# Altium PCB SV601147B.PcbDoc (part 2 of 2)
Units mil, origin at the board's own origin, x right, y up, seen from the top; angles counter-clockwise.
Board outline 2155 x 1865 mil, 4 copper layers (Top Layer, MidLayer1, MidLayer2, Bottom Layer), stack 61.2 mil thick; 86 components, 54 nets, 303 pads, 97 vias.

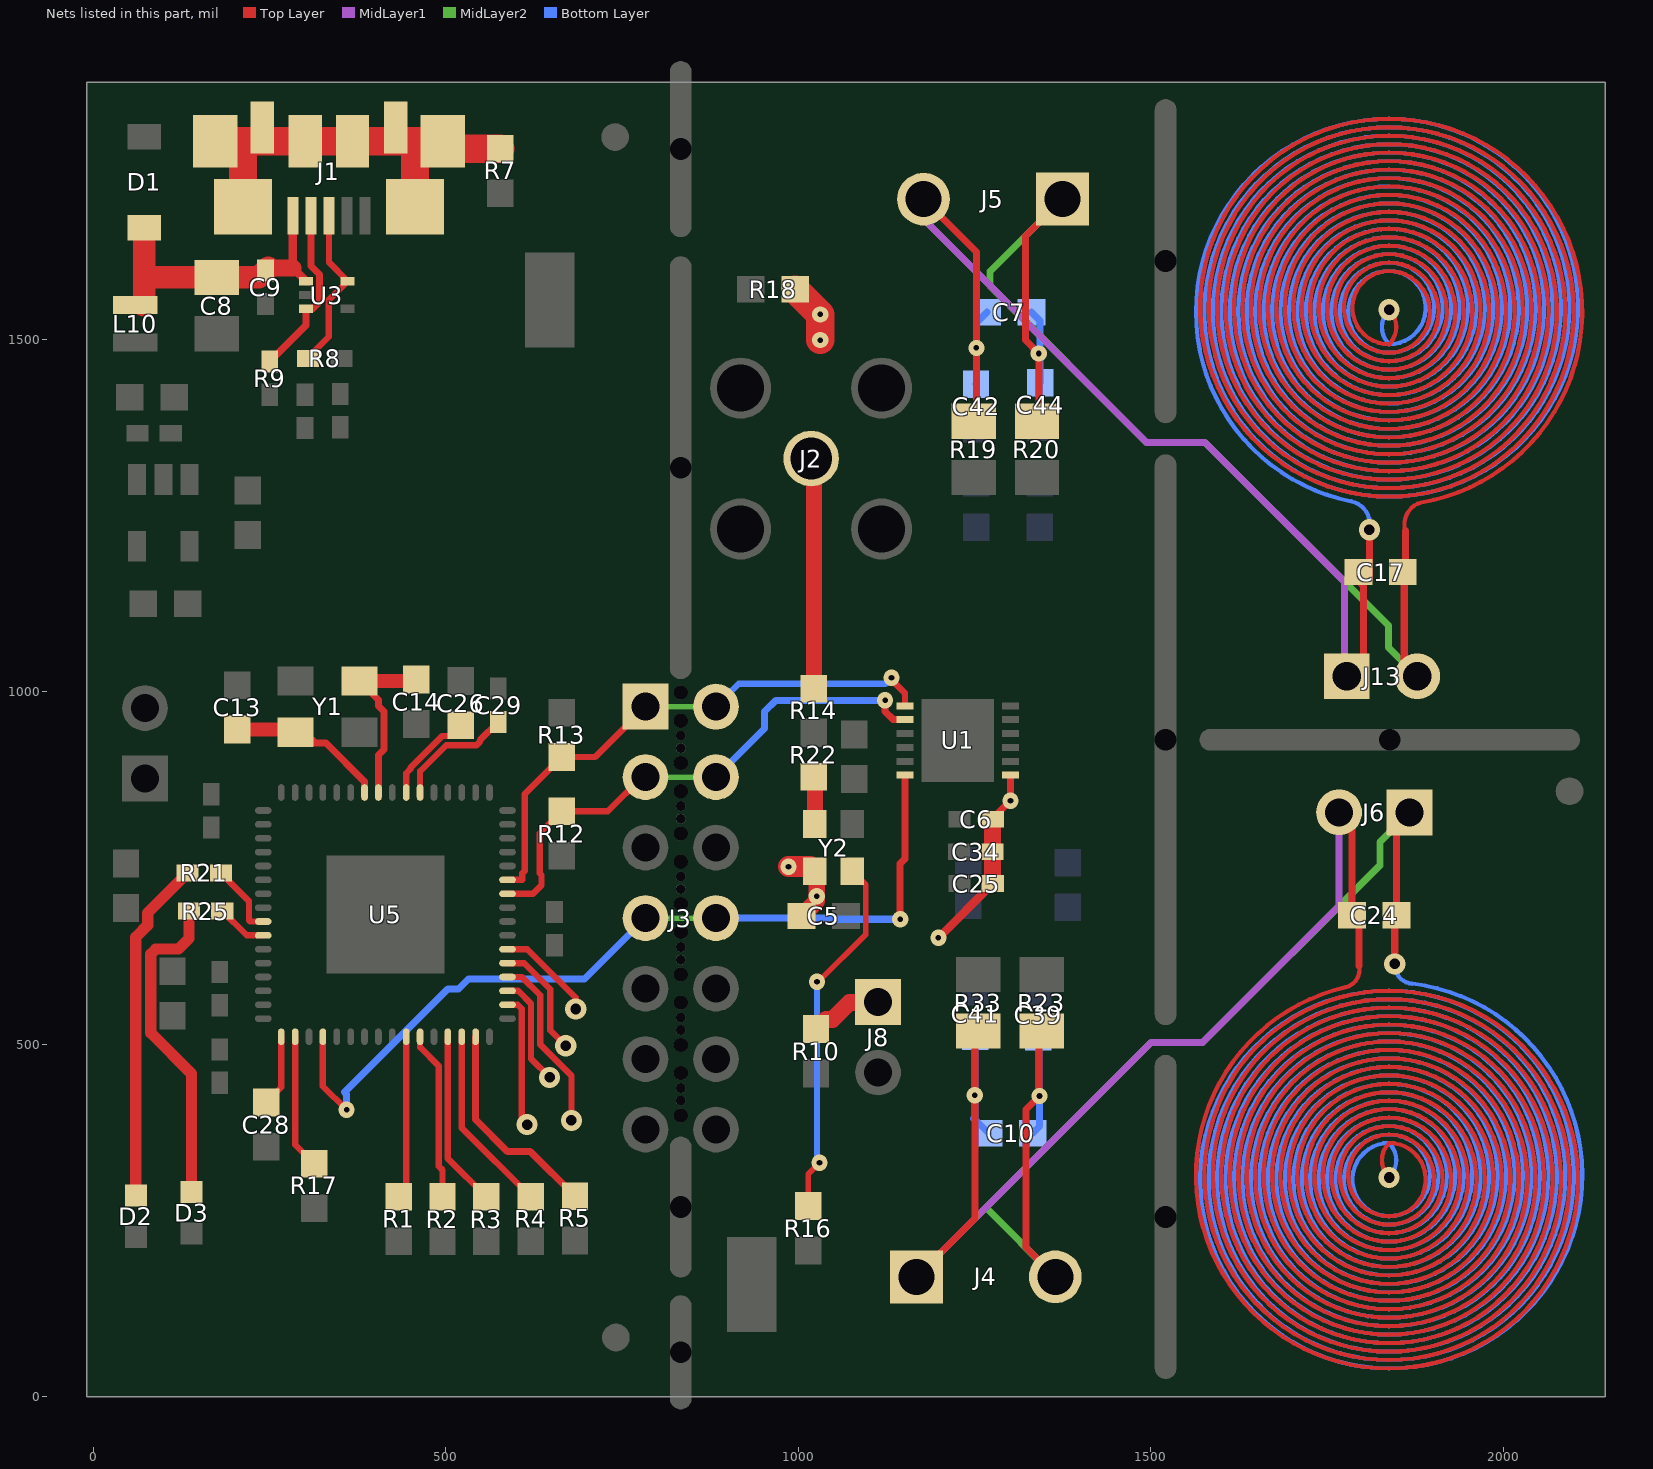
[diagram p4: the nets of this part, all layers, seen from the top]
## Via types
v1: diameter 23, hole 8, Top Layer to Bottom Layer, tented both sides, 58 vias
v2: diameter 19.68, hole 7.87, Top Layer to Bottom Layer, 18 vias
v3: diameter 20, hole 8, Top Layer to Bottom Layer, tented both sides, 8 vias
v4: diameter 30, hole 15, Top Layer to Bottom Layer, 5 vias
v5: diameter 30, hole 15, Top Layer to Bottom Layer, tented both sides, 4 vias
v6: diameter 50, hole 25, Top Layer to Bottom Layer, 2 vias
v7: diameter 50, hole 28, Top Layer to Bottom Layer, 2 vias

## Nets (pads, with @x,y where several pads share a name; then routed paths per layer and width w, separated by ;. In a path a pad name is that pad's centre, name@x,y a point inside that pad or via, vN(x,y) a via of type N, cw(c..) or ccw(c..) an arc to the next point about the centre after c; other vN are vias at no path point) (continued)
NetC7_1: C7.1 C7.2 C17.1 C17.2 C42.2 C44.1 J5.1 J5.2 J13.1 J13.2 R19.2 R20.2 | length 42394.5
  Top Layer w6: v5(1838,1542) cw(c1813.5,1517.5) 1838,1493 cw(c1838,1545) 1838,1597 cw(c1838,1539) 1838,1481 cw(c1838,1545) 1838,1609 cw(c1838,1539) 1838,1469 cw(c1838,1545) 1838,1621 cw(c1838,1539) 1838,1457 cw(c1838,1545) 1838,1633 cw(c1838,1539) 1838,1445 cw(c1838,1545) 1838,1645 cw(c1838,1539) 1838,1433 cw(c1838,1545) 1838,1657 cw(c1838,1539) 1838,1421 cw(c1838,1545) 1838,1669 cw(c1838,1539) 1838,1409 cw(c1838,1545) 1838,1681 cw(c1838,1539) 1838,1397 cw(c1838,1545) 1838,1693 cw(c1838,1539) 1838,1385 cw(c1838,1545) 1838,1705 cw(c1838,1539) 1838,1373 cw(c1838,1545) 1838,1717 cw(c1838,1539) 1838,1361 cw(c1838,1545) 1838,1729 cw(c1838,1539) 1838,1349 cw(c1838,1545) 1838,1741 cw(c1838,1539) 1838,1337 cw(c1838,1545) 1838,1753 cw(c1838,1539) 1838,1325 cw(c1838,1545) 1838,1765 cw(c1838,1539) 1838,1313 cw(c1838,1545) 1838,1777 cw(c1838,1539) 1838,1301 cw(c1838,1545) 1838,1789 cw(c1838,1539) 1838,1289 cw(c1838,1545) 1838,1801 cw(c1838,1539) 1838,1277 cw(c1838,1545) 1838,1813 cw(c1838,1539) 1883.53,1268.81 ccw(c1892.17,1237.64) 1861,1229
  Top Layer w10: J5.2@1177.57,1699 1252.46,1624.12 v1(1252.46,1488) R19.2@1252.46,1381 ; R20.2@1342.46,1384 1341,1385.46 v1(1341,1480) 1322,1499 1322,1646.57 J5.1@1368.71,1693.29 ; J13.1@1777,1003 1777,1004 1802,1029 1802,1149.5 C17.1@1796.5,1155 ; C17.1@1810,1158.5 v5(1810,1230) ; J13.2@1859.5,1020.5 C17.2@1859.5,1155 ; C17.2@1861,1163.5 1861,1229 ; J13.2@1870,1010 J13.2@1877,1003
  MidLayer1 w10: J5.2@1157.57,1690.43 1494,1354 1577,1354 1775,1156 J13.1@1775,1015 ; J5.2@1177.57,1690.43 J5.2@1177.57,1699
  MidLayer2 w10: J5.1@1374.43,1699 1271.71,1596.29 1271.71,1576.71 1271.5,1576.5 1494,1354 1577,1354 1837,1094 1837,1063 J13.2@1878,1022
  Bottom Layer w6: v5(1810,1230) ccw(c1777.09,1237.37) 1784.45,1270.28 cw(c1838,1539) 1838,1813 cw(c1838,1545) 1838,1277 cw(c1838,1539) 1838,1801 cw(c1838,1545) 1838,1289 cw(c1838,1539) 1838,1789 cw(c1838,1545) 1838,1301 cw(c1838,1539) 1838,1777 cw(c1838,1545) 1838,1313 cw(c1838,1539) 1838,1765 cw(c1838,1545) 1838,1325 cw(c1838,1539) 1838,1753 cw(c1838,1545) 1838,1337 cw(c1838,1539) 1838,1741 cw(c1838,1545) 1838,1349 cw(c1838,1539) 1838,1729 cw(c1838,1545) 1838,1361 cw(c1838,1539) 1838,1717 cw(c1838,1545) 1838,1373 cw(c1838,1539) 1838,1705 cw(c1838,1545) 1838,1385 cw(c1838,1539) 1838,1693 cw(c1838,1545) 1838,1397 cw(c1838,1539) 1838,1681 cw(c1838,1545) 1838,1409 cw(c1838,1539) 1838,1669 cw(c1838,1545) 1838,1421 cw(c1838,1539) 1838,1657 cw(c1838,1545) 1838,1433 cw(c1838,1539) 1838,1645 cw(c1838,1545) 1838,1445 cw(c1838,1539) 1838,1633 cw(c1838,1545) 1838,1457 cw(c1838,1539) 1838,1621 cw(c1838,1545) 1838,1469 cw(c1838,1539) 1838,1609 cw(c1838,1545) 1838,1481 cw(c1838,1539) 1838,1597 cw(c1838,1545) 1838,1493 cw(c1862.5,1517.5) v5(1838,1542)
  Bottom Layer w10: C42.2@1252,1436.5 1252.46,1436.95 v1(1252.46,1488) 1252.46,1523.52 C7.2@1267.5,1538.57 ; C7.1@1330.5,1538.57 1342.46,1526.61 1342.46,1439.04 C44.1@1343,1438.5 ; J13.2@1861.33,1012.08 J13.2@1871,1012
NetC10_1: C10.1 C10.2 C24.1 C24.2 C39.2 C41.1 J4.1 J4.2 J6.1 J6.2 R23.2 R33.2 | length 42470.1
  Top Layer w6: 1795.37,610.97 cw(c1770.52,605.69) 1775.8,580.85 ccw(c1838,314) 1838,40 ccw(c1838,308) 1838,576 ccw(c1838,314) 1838,52 ccw(c1838,308) 1838,564 ccw(c1838,314) 1838,64 ccw(c1838,308) 1838,552 ccw(c1838,314) 1838,76 ccw(c1838,308) 1838,540 ccw(c1838,314) 1838,88 ccw(c1838,308) 1838,528 ccw(c1838,314) 1838,100 ccw(c1838,308) 1838,516 ccw(c1838,314) 1838,112 ccw(c1838,308) 1838,504 ccw(c1838,314) 1838,124 ccw(c1838,308) 1838,492 ccw(c1838,314) 1838,136 ccw(c1838,308) 1838,480 ccw(c1838,314) 1838,148 ccw(c1838,308) 1838,468 ccw(c1838,314) 1838,160 ccw(c1838,308) 1838,456 ccw(c1838,314) 1838,172 ccw(c1838,308) 1838,444 ccw(c1838,314) 1838,184 ccw(c1838,308) 1838,432 ccw(c1838,314) 1838,196 ccw(c1838,308) 1838,420 ccw(c1838,314) 1838,208 ccw(c1838,308) 1838,408 ccw(c1838,314) 1838,220 ccw(c1838,308) 1838,396 ccw(c1838,314) 1838,232 ccw(c1838,308) 1838,384 ccw(c1838,314) 1838,244 ccw(c1838,308) 1838,372 ccw(c1838,314) 1838,256 ccw(c1838,308) 1838,360 ccw(c1862.5,335.5) v5(1838,311)
  Top Layer w10: J4.1@1167.57,170 1250.3,252.72 v1(1250.3,427.55) R33.2@1250.3,519 ; v1@1341,427.55 R23.2@1341,521 ; v1(1342,426.55) 1322.71,407.26 1322.71,211.71 J4.2@1364.43,170 ; J6.2@1767,829 1785.5,810.5 C24.1@1785.5,684 ; 1795.37,610.97 C24.1@1795.37,673.14 ; v5(1846,614) C24.2@1846,681.5 ; C24.2@1848.5,683 1848.5,684 1848.5,810.5 J6.1@1867,829
  MidLayer1 w10: J4.1@1167.57,170 1500,502.43 1573.43,502.43 1767,696 J6.2@1767,829
  MidLayer2 w10: J4.2@1364.43,170 1266,268.43 1500,502.43 1573.43,502.43 1825,754 1825,787 J6.1@1867,829
  Bottom Layer w6: v5(1838,311) ccw(c1813.5,335.5) 1838,360 ccw(c1838,308) 1838,256 ccw(c1838,314) 1838,372 ccw(c1838,308) 1838,244 ccw(c1838,314) 1838,384 ccw(c1838,308) 1838,232 ccw(c1838,314) 1838,396 ccw(c1838,308) 1838,220 ccw(c1838,314) 1838,408 ccw(c1838,308) 1838,208 ccw(c1838,314) 1838,420 ccw(c1838,308) 1838,196 ccw(c1838,314) 1838,432 ccw(c1838,308) 1838,184 ccw(c1838,314) 1838,444 ccw(c1838,308) 1838,172 ccw(c1838,314) 1838,456 ccw(c1838,308) 1838,160 ccw(c1838,314) 1838,468 ccw(c1838,308) 1838,148 ccw(c1838,314) 1838,480 ccw(c1838,308) 1838,136 ccw(c1838,314) 1838,492 ccw(c1838,308) 1838,124 ccw(c1838,314) 1838,504 ccw(c1838,308) 1838,112 ccw(c1838,314) 1838,516 ccw(c1838,308) 1838,100 ccw(c1838,314) 1838,528 ccw(c1838,308) 1838,88 ccw(c1838,314) 1838,540 ccw(c1838,308) 1838,76 ccw(c1838,314) 1838,552 ccw(c1838,308) 1838,64 ccw(c1838,314) 1838,564 ccw(c1838,308) 1838,52 ccw(c1838,314) 1838,576 ccw(c1838,308) 1838,40 ccw(c1838,314) 1871,586.01 cw(c1872.5,612.5) v5(1846,614)
  Bottom Layer w10: C41.1@1251,511.5 1250.3,510.8 v1(1250.3,427.55) 1250.3,396.44 1248.68,394.82 C10.2@1269.5,374 ; C10.1@1332.5,374 1342,383.5 v1(1342,426.55) ; C39.2@1340,510.5 1341,509.5 v1@1341,427.55 ; J6.2@1767,829 J6.2@1781,829 ; J6.1@1849,829 J6.1@1864.28,829 ; J6.1@1865.64,830.36 J6.1@1864.28,829 ; J6.1@1867,829 J6.1@1864.28,829
NetC13_2: C13.2 U5.58 Y1.3 | length 226.3
  Top Layer w10: Y1.3@286.72,942.58 299.11,942.58 314.44,927.26 329.64,927.26 384.46,872.43 U5.58@384.46,857.23
  Top Layer w20: C13.2@204,946.5 282.8,946.5 Y1.3@286.72,942.58
NetC14_2: C14.2 U5.57 Y1.1 | length 257.3
  Top Layer w10: Y1.1@377.28,1015.42 404.15,988.54 404.15,979.96 411.87,972.25 411.87,918.19 404.15,910.47 U5.57@404.15,857.23
  Top Layer w20: Y1.1@377.28,1015.42 455.92,1015.42 C14.2@458,1017.5
NetC26_2: C26.2 U5.55 | length 140.8
  Top Layer w9: U5.55@443.54,857.23 443.54,884.53 450.22,891.22 450.22,892.61 494.93,937.32 517.79,937.32 521,940.53 C26.2@521,952.5
NetC28_1: C28.1 U5.17 | length 102.3
  Top Layer w9: C28.1@245,417.5 266.5,439 266.5,510.6 U5.17@266.33,510.77
NetD2_1: D2.1 R21.2 | length 487.9
  Top Layer w16: D2.1@60,285.53 60,652.15 76.7,668.85 76.7,686.32 R21.2@133.38,743
NetD3_1: D3.1 R25.2 | length 463.6
  Top Layer w16: R25.2@135.38,689 135.38,650.13 120.43,635.18 88.33,635.18 81.3,628.15 81.3,515.85 139,458.15 139,304.53 D3.1@139,290.53
NetJ1_2: J1.2 R9.1 U3.3 | length 246.1
  Top Layer w10: R9.1@250,1468.62 301.47,1520.09 U3.3@301.47,1543.32 310.26,1543.32 320.31,1553.37 320.31,1592.32 308.41,1604.22 J1.2@308.41,1675.49
NetJ1_3: J1.3 R8.1 U3.5 | length 236.7
  Top Layer w9: R8.1@304.38,1473 304.38,1474.47 333.81,1503.91 333.81,1555.97 U3.5@360.53,1582.69 334,1609.21 J1.3@334,1675.49
NetJ1_6: J1.6 J1.7 J1.8 J1.9 J1.10 J1.11 J1.12 J1.13 R7.2 | length 725
  Top Layer w40: J1.13@178,1781 J1.8@495.42,1781 ; J1.7@211.95,1688.48 211.95,1779.95 ; 211.95,1781 J1.11@300.54,1781 J1.10@367.46,1781 ; J1.6@456.05,1688.48 456.05,1777.95 ; J1.8@505.92,1770.5 R7.2@577,1770.5
NetJ2_1: J2.1 R14.2 | length 328.2
  Top Layer w23: J2.1@1018,1331 1022,1327 R14.2@1022,1004.5
NetR1_1: R1.1 U5.26 | length 231.6
  Top Layer w9: R1.1@433,283.5 443.54,294.03 U5.26@443.54,510.77
NetR2_1: R2.1 U5.27 | length 240.4
  Top Layer w9: U5.27@463.22,510.77 463.22,495.57 489.61,469.19 489.61,327.11 495,321.72 R2.1@495,283.5
NetR3_1: R3.1 U5.29 | length 249.8
  Top Layer w9: U5.29@502.61,510.77 502.61,337.89 R3.1@557,283.5
NetR4_1: R4.1 U5.30 | length 267.7
  Top Layer w9: U5.30@522.3,510.77 522.3,381.2 R4.1@620,283.5
NetR5_1: R5.1 U5.31 | length 303.7
  Top Layer w10: U5.31@541.98,510.77 541.98,393.02 587,348 619.5,348 R5.1@683,284.5
NetR16_2: R16.2 Y2.1 | length 520.9
  Top Layer w8: R16.2@1014,270.5 1014,316 v1(1030,332) ; v1(1026.4,588.82) 1028.71,588.82 1095.43,655.55 1095.43,726.68 Y2.1@1076.57,745.54
  Bottom Layer w8: v1(1026.4,588.82) 1026.4,335.6 v1(1030,332)
NetR17_1: R17.1 U5.18 | length 191.5
  Top Layer w9: U5.18@286.01,510.77 286.01,357.48 R17.1@313,330.5
NetR21_1: R21.1 U5.9 | length 104.7
  Top Layer w9: R21.1@180.62,743 220.46,703.16 220.46,675.85 222.16,674.16 U5.9@240.77,674.16
NetR22_1: R22.1 Y2.3 | length 67.6
  Top Layer w23: R22.1@1022,879.5 1023.43,878.08 Y2.3@1023.43,812.46
NetR25_1: R25.1 U5.10 | length 72.5
  Top Layer w9: R25.1@182.62,689 217.15,654.47 U5.10@240.77,654.47
P3.0: U5.34 | length 190.2
  Top Layer w9: U5.34@587.23,556.05 601.95,556.05 607.54,550.46 607.54,393.46 v4(615,386)
P3.1: U5.35 | length 156.3
  Top Layer w9: U5.35@587.23,575.73 602.27,575.73 620.54,557.46 620.54,479.46 v4(647,453)
P3.2: U5.36 | length 252.9
  Top Layer w9: U5.36@587.23,595.42 607.58,595.42 633.54,569.46 633.54,499.69 678,455.23 v4(678,392)
P3.3: U5.37 | length 165.3
  Top Layer w9: U5.37@587.23,615.1 610.9,615.1 648,578 648,520 v4(670,498)
P3.4: U5.38 | length 141.3
  Top Layer w9: U5.38@587.23,634.79 615.21,634.79 684,566 v4(684,550)
SCL: J3.1 J3.2 R13.1 U1.1 U5.43 | length 784.9
  Top Layer w9: U5.43@587.23,733.21 608.21,733.21 608.21,742.44 611.54,745.76 611.54,855.04 R13.1@664,907.5 711.5,907.5 J3.1@783,979 ; v1(1132,1020) 1132,1017.39 1151.2,998.2 U1.1@1151.2,980.21
  MidLayer1 w9: v1(1132,1020) v1@1136.14,1020
  MidLayer2 w8: J3.1@783,979 J3.2@883,979
  Bottom Layer w9: J3.2@883,979 915.5,1011.5 1123.5,1011.5 v1(1132,1020)
SD: J3.7 J3.8 U1.6 U5.20 | length 1232.4
  Top Layer w9: U5.20@325.39,510.77 325.39,440.61 v1(359,407)
  Top Layer w10: v1(1144.39,677.39) 1144.39,756.39 1151.2,763.2 U1.6@1151.2,881.79
  MidLayer2 w8: J3.7@783,679 J3.8@873,679
  Bottom Layer w10: v1(359,407) 359,429.08 356.08,432 502.58,578.5 517.8,578.5 531.8,592.5 696.5,592.5 J3.7@783,679 ; J3.8@883,679 944,679 1052,679 1053.61,677.39 v1(1144.39,677.39)
SDA: J3.3 J3.4 R12.1 U1.2 U5.42 | length 759.5
  Top Layer w9: U5.42@587.23,713.53 623.53,713.53 635.46,725.46 635.46,739.98 632.8,742.64 632.8,799.3 R12.1@664,830.5 729.5,830.5 778,879 J3.3@783,879
  Top Layer w10: v1(1123,988) 1123,972 1134.47,960.53 U1.2@1151.2,960.53
  MidLayer2 w8: J3.3@783,879 J3.4@883,879
  Bottom Layer w10: J3.4@883,879 952,948 952,972 968,988 v1(1123,988)
VBUS: C8.1 C9.1 D1.1 J1.1 L10.1 U3.1 | length 429.4
  Top Layer w12: J1.1@282.82,1675.49 282.82,1601.34 U3.1@301.47,1582.69
  Top Layer w24: C9.1@247.72,1601.34 282.82,1601.34
  Top Layer w32: L10.1@71,1548.57 72,1549.57 72,1593.32 ; D1.1@72,1658.53 72,1593.32 ; C9.1@247.72,1601.34 C9.1@244,1597.62 234.38,1588 C8.1@175,1588 77.32,1588 72,1593.32
VDD: C5.1 C6.1 C25.1 C34.1 J8.1 R10.2 R18.2 U1.7 Y2.4 | length 561.4
  Top Layer w10: C6.1@1275.22,820 v1(1300.8,845.58) U1.7@1300.8,881.79
  Top Layer w12: v1(1198.62,651) C25.1@1275.62,728
  Top Layer w24: C5.1@1004.5,682 1026,703.5 1026,742.96 Y2.4@1023.43,745.54 ; R10.2@1025,521.5 1038.83,535.32 1048.56,535.32 1072.42,559.18 1113,559.18 J8.1@1113,560 ; C34.1@1275.22,773 1275.22,728.4 C25.1@1275.62,728 ; C34.1@1275.22,775 1275.22,805.19
  Top Layer w30: v1(986,752) 1016.96,752 Y2.4@1023.43,745.54
  Top Layer w40: R18.2@995.5,1571 v1(1031,1535.5) v1(1031,1499)
  other v1: 1026,710
VUSB: C29.1 U5.54 | length 171.2
  Top Layer w9: U5.54@463.22,857.23 463.22,887.22 500.32,924.32 543.22,924.32 548.2,929.3 548.2,931.58 C29.1@574,957.38
pads on no net: FID1.1 FID2.1 FID3.1 J1.4 LBL1.0 U3.2 U5.1 U5.2 U5.3 U5.4 U5.5 U5.6 U5.7 U5.8 U5.12 U5.13 U5.22 U5.23 U5.24 U5.25 U5.28 U5.32 U5.33 U5.41 U5.44 U5.45 U5.46 U5.47 U5.48

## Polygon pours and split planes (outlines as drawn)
GND on MidLayer1 "Bottom Layer-No Net" (solid, pour order 11): 19.09,-7.34 792.09,-7.34 792.09,1812.66 19.09,1812.66 19.09,-7.34
GND on MidLayer1 "Bottom Layer-No Net" (solid, remove dead copper, pour order 14): 875,35 1541,35 1541,1840 875,1840 875,35
+3.3V on MidLayer2 "Bottom Layer-No Net" (solid, pour order 8): 20,770 790,770 790,1840 20,1840
+3.3V on MidLayer2 "Bottom Layer-No Net" (solid, pour order 10): 17,17 791,17 791,770.5 17,770.5 17,17
+3.3V on MidLayer2 "Bottom Layer-No Net" (solid, remove dead copper, pour order 13): 875,35 1539,35 1539,1840 875,1840 875,35
VDD on MidLayer2 "Bottom Layer-No Net" (solid, remove dead copper, pour order 12): 972.46,510 1388.46,510 1388.46,1725.95 972.46,1725.95
GND on Bottom Layer "Bottom Layer-No Net 1" (solid, remove dead copper, pour order 9): 899,368.67 1399,368.67 1399,1476.67 899,1476.67

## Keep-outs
Keep-Out Layer:
  lines w8: -15,-5 2150,-5 2150,1870 -15,1870 -15,-5
  text ".Layer_Name" at 577,-858.49 h60

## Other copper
Top Layer:
  text ".Layer_Name" at 577,-858.49 h60
MidLayer1:
  pour cut-out: 154.5,894 154.7,894.2 154.7,1052.87 485.63,1052.87 497.5,1040.99 497.5,888
  pour cut-out: 876,1185.33 876,1470 1163.67,1470 1163.67,1186 1163,1185.33
MidLayer2:
  pour cut-out: 154.5,894 154.7,894.2 154.7,1052.87 485.63,1052.87 497.5,1040.99 497.5,888
Bottom Layer:
  text ".Layer_Name" at 577,-858.49 h60
Multi-Layer:
  pour cut-out: 1288,311 ccw(c1838,311) 1838,-239 ccw(c1838,311) 2388,311 ccw(c1838,311) 1838,861 ccw(c1838,311)
  pour cut-out: 1838,992 cw(c1838,1542) 1288,1542 cw(c1838,1542) 1838,2092 cw(c1838,1542) 2388,1542 cw(c1838,1542)

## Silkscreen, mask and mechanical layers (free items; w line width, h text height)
Top Overlay:
  lines w10: 1123,693 1420,693 1420,1086 1123,1086 1123,693
  text "GND" at 897,1808 h30
  text "CH1" at 1334,1454 h60
  text "GND" at 602,1425 h30
  text "SENSOR CH1" at 1670,1264 h55 r90
  text "+5V" at 417,1165 h30
  text "LDC" at 1289,1030 h40
  text "or" at 972.46,946.05 h30 r90
  text "SBW" at 161,898 h25 r90
  text "+3.3V" at 1204,438 h30 r90
  text "CH0" at 1308,351 h60
  text "GND" at 891,255 h30
  text "SENSOR CH0" at 1670,64 h55 r90
  text "GND" at 179,52 h30
  text "ACLK" at 360,43 h30 r90
  text ".Layer_Name" at 577,-858.49 h60
Bottom Overlay:
  region: 267,589 267,889 167,889 167,589
  text ".PRJ_Number" at 267,1805 h60 r90
  text "0.15mm trace width" at 2015,1804 h40 r90
  text "0.15mm trace spacing" at 2073,1804 h40 r90
  text "19 turns/layer" at 1899,1803 h40 r90
  text "2 layers" at 1957,1803 h40 r90
  text "SENSOR: 13.9mm" at 1841,1802 h40 r90
  text ".PCB_Rev" at 267,1292 h60 r90
  text "TCK" at 100,1042 h25
  text "SCL" at 1015,968 h30
  text "SDA" at 1024.37,865 h30
  text "TDIO" at 113,791 h25
  text "©" at 1998,768 h105 r90
  text "ADDR" at 1060.3,762 h30
  text "MADE IN U.S." at 2102,760 h60 r90
  text ".CopyrightYear" at 1986,677 h60 r90
  text "SD" at 1010,660 h30
  text "INTB" at 1045,565 h30
  text "GND" at 1018.25,469.61 h30
  text "3.3V" at 1046,363 h30
  text ".Layer_Name" at 577,-858.49 h60
Top Paste:
  text ".Layer_Name" at 577,-858.49 h60
Bottom Paste:
  text ".Layer_Name" at 577,-858.49 h60
Top Solder:
  text ".Layer_Name" at 577,-858.49 h60
  text ".Layer_Name" at 577,-858.49 h60
Bottom Solder:
  text ".Layer_Name" at 577,-858.49 h60
Drill Guide:
  text ".Layer_Name" at 577,-858.49 h60
M1 Board Outline:
  the board outline again, w8
  text ".Layer_Name" at 577,-858.49 h60
M2 Board Dimensions:
  rectangle: 124.5,-410.5 499.5,-285.5
  rectangle: -0.5,-285.5 124.5,-160.5
  lines w7: -0.5,-285.5 999.5,-285.5 ; 124.5,-410.5 124.5,-160.5 ; 249.5,-410.5 249.5,-160.5 ; 499.5,-410.5 499.5,-160.5 ; 749.5,-410.5 749.5,-160.5 ; -0.5,-410.5 -0.5,-160.5 999.5,-160.5 999.5,-410.5 -0.5,-410.5
  lines w10: -0.5,-475.5 -0.5,-455.5 ; 59.5,-485.5 -0.5,-465.5 ; 59.5,-445.5 -0.5,-465.5 ; 223.58,-465.5 -0.5,-465.5 ; 775.42,-465.5 999.5,-465.5 ; 939.5,-485.5 999.5,-465.5 ; 939.5,-445.5 999.5,-465.5 ; 999.5,-475.5 999.5,-455.5
  text "1000 (mil)" at 233.58,-501.49 h60
  text ".Layer_Name" at 577,-858.49 h60
M3 3D STEP Top:
  text ".Layer_Name" at 577,-858.49 h60
M4 3D STEP Bottom:
  text ".Layer_Name" at 577,-858.49 h60
M5 Assembly Top:
  lines w10: -292,-930.17 6308,-930.17 ; -292,-726.83 6310,-726.83 ; -292,-523.5 -292,-1133.5 3713,-1133.5 6310,-1133.5 6310,-523.5 -291.5,-523.5 -291.5,-1133.5 1284,-1133.5 ; 2173,-1133.5 2173,-523.5 ; 3440,-726.83 3440,-523.5 ; 4280,-726.83 4280,-523.5 ; 4902,-1140 4902,-937.17
  text "COMPONENTS MARKED 'DNP' SHOULD NOT BE POPULATED." at 1153.5,-318.5 h60
  text "ASSEMBLY VARIANT:" at 1153,-434 h60
  text ".VariantName" at 2189,-434 h60
  text "PCB VIEWED FROM TOP SIDE" at -228.5,-655.67 h60
  text "BOARD #:" at 2248,-655.67 h60
  text ".PRJ_Number" at 2793.5,-655.67 h60
  text "REV:" at 3638,-655.67 h60
  text ".PCB_Rev" at 3929.5,-655.67 h60
  text "SVN REV:" at 4476,-655.67 h60
  text ".VersionControl_RevNumber" at 4982,-655.67 h60
  text "IGNORE ->" at -228.5,-858.49 h60
  text "PLOT NAME =" at -228.5,-1064.34 h60
  text ".plot_File_Name" at 577,-1064.34 h60
  text "GENERATED    :" at 2250,-1064.34 h60
  text ".Print_Date" at 3119.5,-1064.34 h60
  text ".Print_Time" at 3848.5,-1064.34 h60
  text "TEXAS INSTRUMENTS" at 5113,-1064.34 h60
M6 Assembly Bottom:
  lines w10: -292.5,-727.33 6309.5,-727.33 ; -290.5,-930.67 6309.5,-930.67 ; 1115.5,-1140.5 1115.5,-937.67 ; 1737.5,-727.33 1737.5,-524 ; 2577.5,-727.33 2577.5,-524 ; 3844.5,-1134 3844.5,-524 ; 4733.5,-1134 6309,-1134 6309,-524 -292.5,-524 -292.5,-1134 2304.5,-1134 6309.5,-1134 6309.5,-524
  text "COMPONENTS MARKED 'DNP' SHOULD NOT BE POPULATED." at 6102,-318 h60
  text ".VariantName" at 5058,-434 h60
  text "ASSEMBLY VARIANT:" at 6097,-434 h60
  text ".VersionControl_RevNumber" at 1035.5,-656.17 h60
  text "SVN REV:" at 1541.5,-656.17 h60
  text ".PCB_Rev" at 2088,-656.17 h60
  text "REV:" at 2379.5,-656.17 h60
  text ".PRJ_Number" at 3224,-656.17 h60
  text "BOARD #:" at 3769.5,-656.17 h60
  text "PCB VIEWED FROM BOTTOM SIDE" at 6246,-656.17 h60
  text "IGNORE ->" at 2547.85,-858.49 h60
  text "TEXAS INSTRUMENTS" at 904.5,-1064.84 h60
  text ".Print_Time" at 2169,-1064.84 h60
  text ".Print_Date" at 2898,-1064.84 h60
  text "GENERATED    :" at 3767.5,-1064.84 h60
  text ".plot_File_Name" at 5440.5,-1064.84 h60
  text "PLOT NAME =" at 6246,-1064.84 h60
M9 Title Sheet:
  drawing of 54 lines, arcs and shapes, not listed
  text "1" at 739.84,8036.5 h70
  text "2" at 3235.5,8036.5 h70
  text "3" at 5724.84,8036.5 h70
  text "4" at 8231.51,8036.5 h70
  text "5" at 10730.5,8036.5 h70
  text "6" at 13235.5,8036.5 h70
  text "A" at -416.5,6893.5 h70
  text "A" at 14383.5,6893.5 h70
  text "B" at -416.5,4513.5 h70
  text "B" at 14383.5,4513.5 h70
  text "C" at -416.5,2138.5 h70
  text "C" at 14383.5,2138.5 h70
  text "PROJECT TITLE:" at 11343.5,277.5 h45
  text ".PRJ_Title" at 11393.5,144.17 h70
  text "DESIGNED FOR:" at 11343.5,-23.5 h45
  text ".PRJ_Customer" at 11393.5,-163.5 h70
  text "D" at -416.5,-231.5 h70
  text "D" at 14383.5,-231.5 h70
  text "FILE NAME:" at 11343.5,-323.5 h45
  text ".PCB_File_Name_No_Path" at 11393.5,-443.5 h70
  text "Texas Instruments (TI) and/or its licensors do not warrant the accuracy or completeness of this specification" at 6374,-605.34 h45
  text "ENGINEER:" at 11343.5,-613.5 h45
  text "LAYOUT BY:" at 12848.5,-613.5 h45
  text "or any information contained therein. TI and/or its licensors do not warrant that this design will meet" at 6329.01,-718 h45
  text ".PRJ_Engineer" at 11393.5,-768.49 h70
  text ".PCB_Layout" at 12899,-768.49 h70
  text "the specifications, will be suitable for your application or fit for any particular purpose, or will operate in" at 6329.01,-830.67 h45
  text ".Layer_Name" at 577,-858.49 h60
  text "ALTIUM DESIGNER VERSION:" at 12848.5,-923.5 h45
  text "an implementation. TI and/or its licensors do not warrant that the design is production worthy. You should" at 6329.01,-943.33 h45
  text "completely validate and test your design implementation to confirm the system functionality for your application." at 6374,-1056 h45
  text ".print_Scale" at 11393.5,-1056.83 h70
  text ".Application_BuildNumber" at 12899,-1056.83 h70
  text "1" at 739.84,-1263.5 h70
  text "2" at 3235.5,-1263.5 h70
  text "3" at 5724.84,-1263.5 h70
  text "4" at 8231.51,-1263.5 h70
  text "5" at 10730.5,-1263.5 h70
  text "6" at 13235.5,-1263.5 h70
M10 Fab Notes:
  drawing of 212 lines, arcs and shapes, not listed
  text "DESIGN INFORMATION" at 12381.02,6810 h60
  text "(REFER ALSO ARRAY/PANEL PROFILING INFORMATION)" at 12019.46,6648.29 h60
  text "BOARD SIZE" at 11333.46,6644 h60
  text "2145MIL" at 11795.78,6516.18 h60
  text "X" at 12301.46,6516.18 h60
  text "1865MIL" at 12532.78,6516.18 h60
  text "Number of Layers :" at 11736.46,6319 h60
  text "4" at 12831.27,6309 h60
  text "MIN. TRACK WIDTH:" at 11736.46,6180 h60
  text "4" at 12832.7,6180 h60
  text "MIL" at 12987.46,6180 h60
  text "MIN. CLEARANCE:" at 11736.46,6048 h60
  text "4" at 12832.7,6048 h60
  text "MIL" at 12987.46,6048 h60
  text "MIN. VIA PAD SIZE:" at 11736.46,5916 h60
  text "20" at 12802.71,5916 h60
  text "MIL" at 12987.46,5916 h60
  text "0.05mm (2MIL)" at 12431.46,5774.29 h60
  text "MINIMUM ANNULAR RING" at 11407.23,5770 h60
  text "EXTERNAL" at 13139.46,5770 h60
  text "PER" at 11607.23,5652 h60
  text "IPC-D-275 CLASS 2 LEVEL C" at 11827.23,5652 h60
  text "MIL, HOLES" at 13315.46,5539.71 h60
  text "+/-" at 12923,5539 h60
  text "+/-" at 13777,5539 h60
  text "REGISTRATION TOLERANCES:" at 11407.23,5534 h60
  text "METAL" at 12607,5534 h60
  text "5" at 13183.2,5534 h60
  text "3" at 14016.2,5534 h60
  text "MIL" at 14132.46,5534 h60
  text "MATERIAL:" at 11332.46,5324.54 h60
  text "FR-4 High Tg" at 12318.9,5184.21 h60
  text "FR-408" at 11753.46,5175.64 h60
  text "X" at 12165.46,5175.64 h60
  text "OTHER" at 13241.46,5175.64 h60
  text "62 MIL (1.6mm) +/-10%" at 12073.56,5012.92 h60
  text "THICKNESS:" at 11407.23,5008.64 h60
  text "X" at 11945.4,5008.64 h60
  text "OTHER" at 13358.46,5008.64 h60
  text "TOLERANCE:" at 11407.23,4850.64 h60
  text "X" at 12246.53,4850.64 h60
  text "ANSI IPC-6012 TYPE 3 CLASS 2" at 12433.48,4850.64 h60
  text "OTHER +/-" at 12433.46,4694.64 h60
  text "BOW & TWIST:" at 11407.23,4537.64 h60
  text "X" at 12246.53,4537.64 h60
  text "ANSI IPC-6012 TYPE 3 CLASS 2" at 12433.48,4537.64 h60
  text "OTHER +/-" at 12433.46,4379.13 h60
  text "COPPER THICKNESS (FINISHED):" at 11332.46,4243.64 h60
  text "1.4MIL (1oz)" at 12212.46,4090.92 h60
  text "2MIL (1.4oz)" at 12979.46,4090.92 h60
  text "2.8MIL (2oz)" at 13706.46,4090.92 h60
  text "OUTER:" at 11689.46,4086.64 h60
  text "X" at 12084,4086 h60
  text "1.4MIL (1oz)" at 12212.46,3933.92 h60
  text "2.8MIL (2oz)" at 12979.46,3933.92 h60
  text "N/A" at 13706,3934.29 h60
  text "INNER SIGNAL:" at 11400.38,3929.64 h60
  text "X" at 12085.42,3929.64 h60
  text "DRILLING:" at 11332.46,3790.64 h60
  text "REFERENCE:" at 11407.23,3673.64 h60
  text "X" at 12055.46,3673.64 h60
  text "AS SHOWN" at 12242.46,3673.64 h60
  text "X" at 12956.46,3673.64 h60
  text "NC_DRILL FILES" at 13093.46,3673.64 h60
  text "PTH MIN COPPER THICKNESS:" at 11407.23,3515.64 h60
  text "X" at 12757.46,3515.64 h60
  text "1MIL" at 12894.46,3515.64 h60
  text "OTHER" at 13391.46,3515.64 h60
  text "BOARD FINISH:" at 11332.46,3356.64 h60
  text "SILKSCREEN:" at 11487.68,3238.64 h60
  text "X" at 12436.46,3238.64 h60
  text "TOP" at 12562.46,3238.64 h60
  text "X" at 12946.46,3238.64 h60
  text "BOTTOM" at 13073.46,3238.64 h60
  text "SILKSCREEN COLOR:" at 11487.68,3071.64 h60
  text "X" at 12435.42,3071.64 h60
  text "WHITE" at 12562.46,3071.64 h60
  text "OTHER" at 13073.46,3071.64 h60
  text "SOLDER RESIST COLOR:" at 11487.68,2901.64 h60
  text "X" at 12055.42,2742.44 h60
  text "GREEN" at 12182.46,2742.44 h60
  text "BLUE" at 12773.46,2742.44 h60
  text "OTHER" at 13311.46,2742.44 h60
  text "IMMERSION GOLD (ENIG)" at 12393.46,2553.92 h60
  text "ENEPIG" at 13731,2550.64 h60
  text "SURFACE FINISH:" at 11332.46,2549.64 h60
  text "X" at 12206.51,2549.64 h60
  text "IMM. TIN/SILVER OR EQUIV" at 11662,2392.64 h60
  text "OTHER" at 13093.46,2392.64 h60
  text "ARRAY/PANEL:" at 11332.46,2213.64 h60
  text "CUT AND TRIM PER MECH LAYER 1" at 12393.46,2209.35 h60
  text "X" at 12209,2062 h60
  text "N.C. ROUTE" at 12393.46,2057.64 h60
  text "V. SCORE" at 13259.46,2057.64 h60
  text "CERTIFICATION:" at 11332.46,1920.64 h60
  text "MATERIALS AND WORKMANSHIP FOR ALL PCBS" at 12057.46,1920.64 h60
  text "TO MEET OR EXCEED THE REQUIREMENTS OF:" at 12057.46,1822.64 h60
  text "X" at 11683.96,1686.13 h60
  text "ANSI IPC-A-600F CLASS ->" at 11822.96,1686.13 h60
  text "X" at 13462.02,1686.13 h60
  text "2" at 13580.96,1686.14 h60
  text "1" at 13265.96,1684.64 h60
  text "3" at 13934.96,1684.64 h60
  text "X" at 11686.02,1526.64 h60
  text "UL 94V-0" at 11822.96,1526.64 h60
  text "X" at 12498.02,1526.64 h60
  text "RoHS" at 12634.96,1526.64 h60
  text "OTHER" at 13279.36,1526.64 h60
  text "PER ORDER" at 13676.42,1526.64 h60
  text "ADDITIONAL REQUIREMENTS:" at 11332.46,1385.64 h60
  text "MICROSECTION:" at 11407.23,1270.64 h60
  text "YES" at 12312.96,1270.64 h60
  text "REQUIRED" at 13174.46,1114.49 h60
  text "BARE BOARD ELEC. TEST:" at 11407.23,1111.64 h60
  text "NONE" at 12712.96,1111.64 h60
  text "X" at 13047.46,1111.64 h60
  text "PER ORDER" at 13766.46,1111.64 h60
  text "MANUFACTURER'S UL:" at 11407.23,954.64 h60
  text "RAIL" at 12572.96,950.35 h60
  text "METAL" at 13064.77,950.35 h60
  text "X" at 13440,950 h60
  text "SILK" at 13576.46,950.35 h60
  text ".Layer_Name" at 577,-858.49 h60
M11 Gerber Information:
  lines w10: -292,-930.17 6308,-930.17 ; -292,-726.83 6310,-726.83 ; -292,-523.5 -292,-1133.5 3713,-1133.5 6310,-1133.5 6310,-523.5 -291.5,-523.5 -291.5,-1133.5 1284,-1133.5 ; 2173,-1133.5 2173,-523.5 ; 3440,-726.83 3440,-523.5 ; 4280,-726.83 4280,-523.5 ; 4902,-1140 4902,-937.17
  text "ALL ARTWORK VIEWED FROM TOP SIDE" at -228.5,-655.67 h60
  text "BOARD #:" at 2248,-655.67 h60
  text ".PRJ_Number" at 2793.5,-655.67 h60
  text "REV:" at 3638,-655.67 h60
  text ".PCB_Rev" at 3929.5,-655.67 h60
  text "SVN REV:" at 4476,-655.67 h60
  text ".VersionControl_RevNumber" at 4982,-655.67 h60
  text "LAYER NAME =" at -228.5,-858.49 h60
  text "PLOT NAME =" at -228.5,-1064.34 h60
  text ".plot_File_Name" at 577,-1064.34 h60
  text "GENERATED    :" at 2250,-1064.34 h60
  text ".Print_Date" at 3119.5,-1064.34 h60
  text ".Print_Time" at 3848.5,-1064.34 h60
  text "TEXAS INSTRUMENTS" at 5113,-1064.34 h60
M12 Stackup:
  lines w6: 11365,7632.25 14230,7632.25 ; 11365,7744.85 14230,7744.85 ; 11286,6907 ccw(c11322,6907) 11322,6871 14235,6871 ccw(c14235,6907) 14271,6907 14271,7902 ccw(c14235,7902) 14235,7938 11322,7938 ccw(c11322,7902) 11286,7902 11286,6907
  text "Layer Stack Up Detail for: SV601147B.PcbDoc" at 11346,7819.02 h58
  text "Layer" at 11365,7702.85 h26
  text "Gerber" at 12072.2,7702.85 h26
  text "Copper" at 12433.65,7702.85 h26
  text "Dielectric" at 12837.55,7702.85 h26
  text "Dielectric" at 13259.64,7702.85 h26
  text "Dielectric" at 13786.9,7702.85 h26
  text "Name" at 11365,7650.85 h26
  text "Document" at 12072.2,7650.85 h26
  text "Thickness" at 12433.65,7650.85 h26
  text "Height" at 12837.55,7650.85 h26
  text "Material" at 13259.64,7650.85 h26
  text "Type" at 13786.9,7650.85 h26
  text "Top Solder Mask" at 11365,7573.68 h36
  text "(.GTS)" at 12072.2,7573.68 h36
  text "0.4mil" at 12837.55,7573.68 h36
  text "Solder Resist" at 13259.64,7573.68 h36
  text "Top Layer" at 11365,7462.53 h36
  text "(.GTL)" at 12072.2,7462.53 h36
  text "1.4mil" at 12433.65,7462.53 h36
  text "12.6mil" at 12837.55,7406.96 h36
  text "FR-4" at 13259.64,7406.96 h36
  text "Core" at 13786.9,7406.96 h36
  text "MidLayer1" at 11365,7351.39 h36
  text "(.G1)" at 12072.2,7351.39 h36
  text "1.4mil" at 12433.65,7351.39 h36
  text "30.4mil" at 12837.55,7295.81 h36
  text "FR-4" at 13259.64,7295.81 h36
  text "PrePreg" at 13786.9,7295.81 h36
  text "MidLayer2" at 11365,7240.24 h36
  text "(.G2)" at 12072.2,7240.24 h36
  text "1.4mil" at 12433.65,7240.24 h36
  text "12.6mil" at 12837.55,7184.67 h36
  text "FR-4" at 13259.64,7184.67 h36
  text "Core" at 13786.9,7184.67 h36
  text "Bottom Layer" at 11365,7129.09 h36
  text "(.GBL)" at 12072.2,7129.09 h36
  text "1.4mil" at 12433.65,7129.09 h36
  text "Bottom Solder Mask" at 11365,7017.95 h36
  text "(.GBS)" at 12072.2,7017.95 h36
  text "0.4mil" at 12837.55,7017.95 h36
  text "Solder Resist" at 13259.64,7017.95 h36
  text ".Layer_Name" at 577,-858.49 h60
M13 Component Bodies Top:
  text ".Layer_Name" at 577,-858.49 h60
M14 Component Bodies Bottom:
  text ".Layer_Name" at 577,-858.49 h60
M15 Courtyards Top:
  text ".Layer_Name" at 577,-858.49 h60
M16 Courtyards Bottom:
  text ".Layer_Name" at 577,-858.49 h60
Drill Drawing:
  text ".legend" at 3286,1076 h40
  text ".Layer_Name" at 577,-858.49 h60

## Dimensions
0,0 to 2145,0 on M2 Board Dimensions
0,0 to -10,1865 on M2 Board Dimensions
